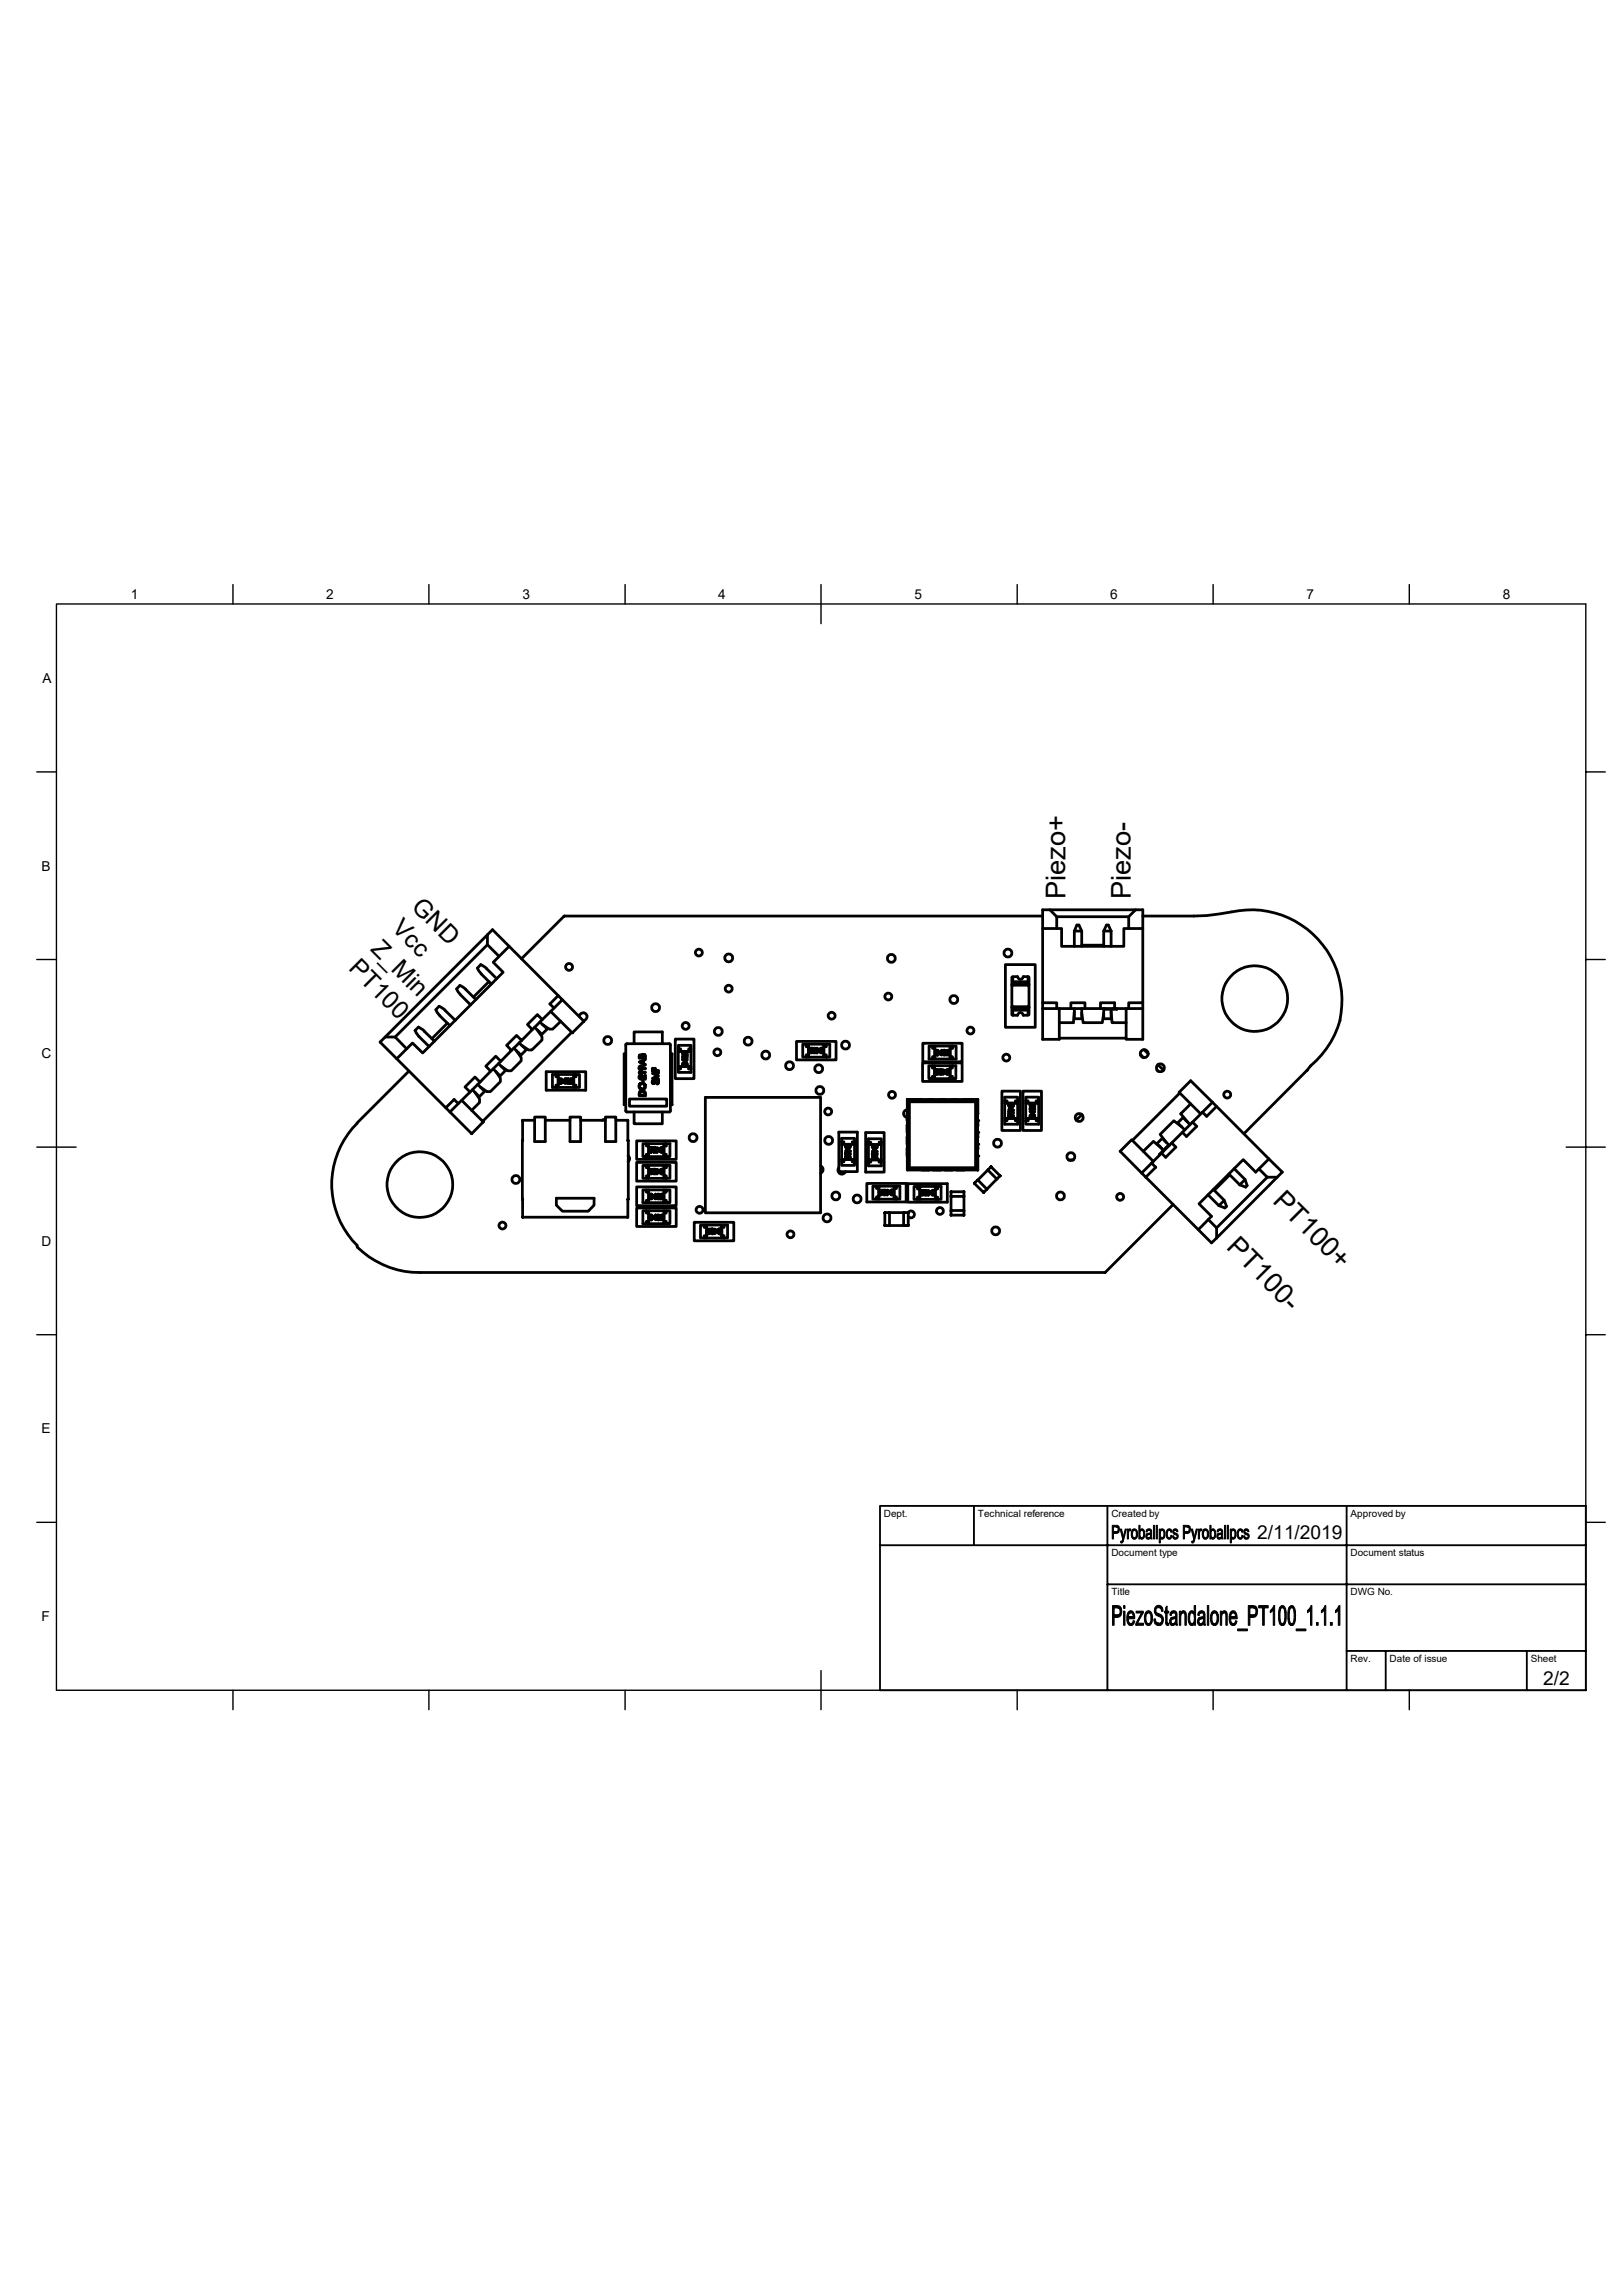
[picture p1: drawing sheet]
<svg xmlns="http://www.w3.org/2000/svg" width="297mm" height="420mm" viewBox="0 0 297 420" stroke-linecap="round" stroke-linejoin="round" font-family="sans-serif">
<defs><g id="words">
<g font-size="5">
<text x="195" y="164.6" transform="rotate(-90 195 164.6)">Piezo+</text>
<text x="207" y="164.6" transform="rotate(-90 207 164.6)">Piezo-</text>
<text x="232.7" y="220" transform="rotate(45 232.7 220)">PT100+</text>
<text x="224.2" y="228.5" transform="rotate(45 224.2 228.5)">PT100-</text>
</g>
<g font-size="4.5">
<text x="75.1" y="166.1" transform="rotate(45 75.1 166.1)">GND</text>
<text x="67.6" y="173.8" transform="rotate(45 67.6 173.8)">Z_Min</text>
<text x="71.5" y="170.1" transform="rotate(45 71.5 170.1)">Vcc</text>
<text x="63.6" y="177.4" transform="rotate(45 63.6 177.4)">PT100</text>
</g>
<g font-size="3.5">
<text x="230.1" y="281.7">2/11/2019</text>
<text x="282.4" y="308.4">2/2</text>
</g>
<g font-size="2.5">
<text x="24" y="109.6">1</text>
<text x="59.7" y="109.6">2</text>
<text x="95.6" y="109.6">3</text>
<text x="131.4" y="109.6">4</text>
<text x="167.3" y="109.6">5</text>
<text x="203.2" y="109.6">6</text>
<text x="239.1" y="109.6">7</text>
<text x="275" y="109.6">8</text>
<text x="7.7" y="125">A</text>
<text x="7.6" y="159.3">B</text>
<text x="7.6" y="193.7">C</text>
<text x="7.6" y="228">D</text>
<text x="7.6" y="262.3">E</text>
<text x="7.6" y="296.6">F</text>
</g>
<g font-size="1.8">
<text x="161.8" y="277.6">Dept.</text>
<text x="178.9" y="277.6">Technical reference</text>
<text x="203.4" y="277.6">Created by</text>
<text x="247.1" y="277.6">Approved by</text>
<text x="203.4" y="284.8">Document type</text>
<text x="247.1" y="284.8">Document status</text>
<text x="203.4" y="292">Title</text>
<text x="247.1" y="292">DWG No.</text>
<text x="247.1" y="304.2">Rev.</text>
<text x="254.3" y="304.2">Date of issue</text>
<text x="280.1" y="304.2">Sheet</text>
</g>
</g></defs>
<g fill="none" stroke="#000" stroke-width=".51">
<path d="M89.2 172.9l-16.9 16.9M89.2 171.1l-18.7 18.7M89.5 179.6l-2.8 2.9M90.9 179.1l-1.9-1.9-1-.7-.6 .7 .1 .3 .5 .6 1.9 2M93.2 173.2l-3.1-3.1-.9 1v1.8l2.1 2.1M184 176.5h5.4v11.5h-5.4zM185.3 178.8h-.1v1.3M186.2 178.7h-.9v1h2.8v-1h-.8M186.2 178.7a.51 .51 0 0 0 .5 .5 .51 .51 0 0 0 .5-.5M188.1 178.8h.2v1.3M190.8 169.9h3.5v3.3h11.4v-3.3h3.4v13.6h-2.6v1.1M190.8 167.6h-87.5l-7.9 7.9"/>
<path d="M192.1 166.5l1.3 1.3v2.1M193.4 167.8h13.1M196.6 170.4v2.8M197.1 169.3h.3l.6 1.1h-1.4zM198 170.4v2.8M198 173h4M202 170.4v2.8M202.5 169.3h.3l.5 1.1h-1.3zM203.3 170.4v2.8M206.5 169.9v-2.1l1.3-1.3h1.3v3.4M207.8 166.5h-17v23.7h3v-5.6M209.1 167.6h9.4a51 51 0 0 0 8.2-.9 16.6 16.6 0 0 1 18.5 20"/>
<path d="M72.6 193.8l2.9-2.9 1.8 1.8 14.8-14.8-1.8-1.8 2.9-2.9 9 9-1.6 1.5 .8 .8-2.2 2.1-.9-.9-1.8 1.8 .9 .9-1.9 2-1-.9-1.8 1.8 .9 .9-1.9 2-1-.9-1.8 1.8 .9 .9-2 2-.9-.9-1.8 1.8 .9 1-2.1 2.1-.8-.8-1.5 1.5M74.4 191.9l-2.1-2.1h-1.8l-.9 .9 16.7 16.8 2.1-2.2-3.9-3.9M74.8 196l-9.5 9.5M79.5 190.5l-2.1-2-.8-.5-.7 .6 .3 .5 2.3 2.4M81.9 187.2l-2.9 2.9M83.3 186.7l-2.1-2-.9-.5-.5 .6 .1 .4 .6 .7 1.8 1.8M86.9 199.9l.9 1.2v.7l-1.5 1.4M87.1 182.9l-1.9-1.9-1-.7-.6 .7 .1 .4 2.4 2.5M87.4 198.5l1.3 1.2-1 1-1.3-1.3M87.8 198l-1.8 1.9M90.7 196.1l.9 1.2v.7l-1.9 1.8h-.6l-1.2-.9M91.2 194.6l1.3 1.3-1 1-1.2-1.3"/>
<path d="M91.7 194.2l-1.9 1.8M94.5 192.3l.9 1.2v.6l-1.8 1.9h-.7l-1.2-.9M95 190.8l1.3 1.3-1 1-1.3-1.3M95.5 190.4l-1.9 1.8M98.3 188.5l.9 1.2v.6l-1.9 1.9h-.6l-1.2-.9M98.8 187l1.3 1.3-1 1-1.3-1.3M99.2 186.6l-1.8 1.8M99.9 196.1h7.3v3.4h-7.3zM101.7 196.6v.5h.5v1.5h-.5v.4M102.2 196.6h2.8v2.4h-2.8zM102.2 182.2l.7 .8-1.5 1.5M102.2 196.6h-1.1v2.4h1.1"/>
<path d="M102.3 197.6l.2-.2a.45 .45 0 0 1 .4 .4 .45 .45 0 0 1-.4 .5 .52 .52 0 0 1-.2-.7zM102.4 197.6l.3-.1 .1 .1v.5l-.1 .1-.3-.1zM102.6 186.9l-1.5 1.4h-.6l-1.2-.8M102.9 183l3.9 3.9-2.1 2.1-3.9-3.9M103.4 197.6v.4h-.3zM103.4 197.4l.1 .7-.1 .2v-.2h-.4zM103.7 197.6l.1-.1h.3v.5l-.1 .2-.3-.1zM103.8 197.4h.3l.1 .4a.34 .34 0 0 1-.1 .4 .34 .34 0 0 1-.4 0l-.1-.6zM104.4 197.4h.3l.2 .2-.1 .2-.3 .4 .4 .1h-.6l.5-.6-.1-.2-.4 .2zM104.6 188.9l-16.3 16.3M105 197.1h.4v-.5h.6v2.4h-.6v-.4h-.4zM105 199h.4"/>
<path d="M105 196.6h.4M106 186a.72 .72 0 0 1 .7-.7 .72 .72 0 0 1 .7 .7 .72 .72 0 0 1-.6 .8M114.5 192.9h-.3v9.3h.3M114.6 191.1h8v12.4h-8zM116 191v-2.2h5.2v2.2M117 194.4l1.1-.6v.1l-.4 .2v.5l.4 .2v.1zM117 196.2l1.1 .1h-1v.2zM117 195.2l.4-.1 .7 .4v.1l-.5-.3v.3a.36 .36 0 0 1-.4 .2 .36 .36 0 0 1-.3-.3zM117 196.9l.4-.1 .6 .5v-.5h.1v.7l-.7-.6-.3 .1v.3l.2 .2-.2-.1-.2-.2zM117 193.1l.3-.1 .2 .2 .1-.2h.3l.2 .3v.3h-1.1zM117.1 193.2l.2-.1 .1 .4h-.3zM117.1 199.7a.62 .62 0 0 1 1 .5v.3h-1.1z"/>
<path d="M117.1 195.2a.26 .26 0 0 1 .4 .1 .26 .26 0 0 1-.2 .4l-.2-.2zM117.2 194.4l.4-.3v.5zM117.2 199.8l.2-.1h.4l.2 .3v.4h-.9zM117.6 197.7h.1v.4h-.1zM117.6 193.1h.3l.1 .4h-.4zM119.3 197.9l.2-.2 .1 .1-.1 .4h.2a.57 .57 0 0 1 .7-.4l.1 .4-.2 .2v-.6h-.2l-.5 .5-.2-.1zM119.4 195.5l.1 .4h.3l.1-.4v.4h.6v.1h-1.1zM119.4 196.4l1.1-.1v.1l-.8 .1 .8 .4-.8 .4 .8 .2-1.1-.1 .9-.5zM122.7 192.9h.3v9.3h-.3M123.6 190.2h3.4v7.2h-3.4zM124.1 192.4h2.3v2.8h-2.3zM124.1 191.3h2.3v.6h-.4v.5h-1.5v-.5h-.4z"/>
<path d="M124.1 195.6h.4v-.4h1.5v.4h.4M124.1 191.9v.5M124.1 195.2v.4M124.9 192.6l.3-.1 .4 .4v-.4h.2v.6l-.6-.5-.2 .1 .1 .3h-.1zM124.9 193.9l.7-.1 .2 .2h-.2v.4zM124.9 194.6l.2-.1a.46 .46 0 0 1 .7 .4l-.5 .2a.37 .37 0 0 1-.4-.5zM124.9 193.3l.7-.1 .2 .3-.2 .2h-.5l-.2-.2zM125 194.7l.1-.1h.5l.1 .2-.1 .1-.4 .1-.2-.1zM125 193.3h.1a.38 .38 0 0 1 .6 .2l-.1 .1h-.5l-.1-.1zM125.1 194h.4v.2zM126.4 195.2v1.1h-2.3v-.7M126.4 191.9v.5"/>
<path d="M145.8 190.6h7.2v3.4h-7.2zM146.9 191.1h.6v.5h.5v1.4h-.5v.5h-.6zM147.5 191.1h.5M147.5 193.5h.5M148 191.1h2.7v2.4h-2.7zM148.1 191.8h.5l-.4 .5 .1 .3 .3-.2-.1 .3-.4-.1 .1-.4 .3-.3zM148.8 191.9h.1a.43 .43 0 0 1 .5 .4 .43 .43 0 0 1-.5 .4l-.2-.3zM148.8 192l.3-.1 .1 .2-.1 .5-.3-.2zM149.5 191.8l.1 .2h.4l-.5 .7-.1-.6zM149.6 192.1h.2l-.2 .4zM150.2 191.9l.3-.1 .1 .2v.5l-.1 .2-.4-.2zM150.2 191.9h.2l.1 .1v.5l-.1 .1h-.2l-.1-.2z"/>
<path d="M150.7 191.1h1.1v2.4h-.6M150.7 193.5h.5M151.2 191.1v.5h-.5v1.4h.5v.5M168.8 194.5h7.3v3.4h-7.3zM168.9 190.9h7.2v3.4h-7.2zM170 195h.6v.5h.4v1.5h-.4v.4h-.6zM170.6 195h.4M170.6 197.4h.4M170.6 191.4v.5h.5v1.5h-.5v.4M170.6 191.4h-.6v2.4h1.1M170.6 191.4h.5M171 195h2.9v2.4h-2.9z"/>
<path d="M171.1 191.4h2.8v2.4h-2.8zM171.2 195.7h.5l-.5 .6 .2 .3 .3-.3-.1 .3a.29 .29 0 0 1-.5-.1 .29 .29 0 0 1 .2-.5l.2-.2zM171.3 192.3l.3-.1 .2 .2-.1 .6-.3 .1a.39 .39 0 0 1-.2-.7zM171.3 192.4l.1-.1a.34 .34 0 0 1 .3 .4 .34 .34 0 0 1-.3 .3zM171.9 195.8l.2-.1 .2 .1 .1 .6a.32 .32 0 0 1-.4 .2 .32 .32 0 0 1-.2-.4zM172 195.8l.3 .2v.4l-.2 .2-.2-.3zM172.3 192.4v.4h-.3zM172.3 192.2v.6l.2 .1-.2 .2v-.2h-.4zM172.6 195.7v.3h.5l-.5 .6-.1-.6zM172.6 192.3l.3-.1 .2 .2v.5l-.2 .2-.3-.2zM172.6 196h.3l-.3 .4zM172.6 192.4l.2-.1 .2 .1v.5a.22 .22 0 0 1-.2 .1 .22 .22 0 0 1-.2-.2z"/>
<path d="M173.2 195.8l.2-.1 .3 .1a.51 .51 0 0 1-.2 .8l-.3-.1zM173.2 192.4a.29 .29 0 0 1 .5-.1 .29 .29 0 0 1-.1 .4l-.2 .3 .4 .1h-.6l.5-.6-.1-.2h-.2l-.1 .2zM173.3 195.8h.2l.2 .2-.1 .4-.2 .2-.2-.2zM173.9 191.9h.4v-.5h.7v2.4h-.7v-.4h-.4zM173.9 195h1v2.4h-.6M173.9 193.8h.4M173.9 191.4h.4M173.9 197.4h.4M174.3 195v.5h-.4v1.5h.4v.4M183.3 199.7h3.4v7.2h-3.4zM185.2 180.3h3.1v3.9h-3.1zM185.2 184.2v.2h3.1"/>
<path d="M185.2 180.3v-.2h3.1v.2M185.2 184.4v1.3h.1M186.2 185.8h-.9v-.9h2.8v.9h-.8M186.2 185.8a.51 .51 0 0 1 .5-.5 .51 .51 0 0 1 .5 .5M187.2 199.7h3.4v7.2h-3.4zM188.3 184.4v1.3h-.2M188.3 184.2v.2M190.8 183.5h2.6v1.1M190.8 184.6h18.3M193.8 190h12.3M196 184.6v-1.1h2.5v1.1M196.6 184.6v1.8h1.4v-1.8"/>
<path d="M196.6 185.1l-.2 2.1h-2.6M198 185.4l.2 1.8h3.5l.3-1.8M201.4 184.6v-1.1h2.6v1.1M202 184.6v1.8h1.3v-1.7M202.1 184.6v.1h1.5M203.3 185.1l.2 2.1h2.6M203.6 184.6v.1h.8v-.1M208.7 192.9l.6 .7M209.1 183.5v6.7h-3v-5.6M209.3 192.1l.8 .8M211.7 195.8l.2 .2M211.9 194.8l1 1.1"/>
<path d="M245.2 186.7a16.9 16.9 0 0 1-5.4 8.4l-.6 .8-11.6 11.6M65.4 205.6a15.7 15.7 0 0 0 0 22.3M83.9 202l-1.6 1.5M95.6 219.4v3.4h19.3v-3.4M95.7 208.7v10.8M97.8 204.4h2v4.5h-2zM97.8 205h-2.2v3.8M99.8 205h4.5M101.8 219.3h6.9v1.3l-1 1.1h-4.8l-1.1-1.1zM104.3 204.4h2v4.5h-2zM106.3 205h4.5M110.7 204.9l-.5 .1"/>
<path d="M110.8 204.4h1.9v4.5h-1.9zM112.7 205h2.2v3.8M114.9 208.7v10.8M114.9 211.5a.66 .66 0 0 1 0 1.1M115.2 201.1h6.8v1.3h-6.8zM116 203.5v2.2h5.2v-2.2M116.5 217.2h7.2v3.4h-7.2zM116.5 212.7h7.2v3.5h-7.2zM116.5 208.8h7.2v3.4h-7.2zM117.6 213.3h.7v.4h.4v1.5h-.4v.4h-.7zM117.6 209.3h.7v.4h.4v1.5h-.4v.5h-.7zM118.3 217.8v.4h.4v1.5h-.4v.4"/>
<path d="M118.3 217.8h-.7v2.3h1.1M118.3 213.3h.4M118.3 209.3h.4M118.3 217.8h.4M118.3 215.6h.4M118.3 211.7h.4M118.7 217.8h2.8v2.3h-2.8zM118.7 213.3h2.8v2.3h-2.8zM118.7 209.3h2.8v2.4h-2.8zM118.8 214h.6l-.5 .5 .1 .3h.2l.1-.2-.1 .2-.4-.1v-.2l.4-.4zM118.8 210h.6l-.5 .5 .1 .3h.2l.1-.2-.2 .3a.28 .28 0 0 1-.2-.2 .28 .28 0 0 1 0-.3l.3-.3zM118.9 218.7l.1-.2 .4 .2v.5l-.1 .2h-.3l-.1-.2z"/>
<path d="M119 218.7l.2-.1 .1 .2-.1 .5-.3-.1zM119.5 214h.2a.47 .47 0 0 1 .4 .2 .47 .47 0 0 1-.1 .5l-.1 .1-.4-.1zM119.5 210.1l.3-.1 .2 .1a.54 .54 0 0 1-.3 .8 .56 .56 0 0 1-.2-.8zM119.6 214.1l.2-.1 .2 .2v.4l-.2 .2-.3-.2zM119.6 210.1h.2l.2 .1-.1 .6h-.3l-.1-.2zM119.9 218.7v.4h-.2zM120 218.5v.6l.1 .1h-.1l-.1 .2v-.2h-.4zM120.2 214l.1 .2h.4l-.5 .6zM120.2 210l.1 .2h.4l-.5 .7zM120.3 218.6a.45 .45 0 0 1 .5 .3 .45 .45 0 0 1-.2 .5l-.4-.2zM120.3 218.7h.1a.31 .31 0 0 1 .3 .3 .31 .31 0 0 1-.4 .2zM120.3 214.2h.3l-.3 .4z"/>
<path d="M120.3 210.3h.3l-.3 .4zM120.9 214.1l.1-.1 .3 .1a.47 .47 0 0 1-.2 .7l-.3-.1zM120.9 210.1l.1-.1 .3 .1 .1 .6a.28 .28 0 0 1-.4 .2 .28 .28 0 0 1-.2-.3zM120.9 214.2l.1-.2 .3 .2v.4l-.1 .2-.3-.1zM120.9 210.2l.2-.1 .2 .1-.1 .6-.3-.1zM120.9 218.6h.5v.3l-.4 .4h.4v.1h-.6l.5-.5-.1-.3-.3 .2zM121.5 218.2h.4v-.4h.7v2.3h-.7v-.4h-.4zM121.5 213.3h1.1v2.3h-.7M121.5 209.3h1.1v2.4h-.7M121.5 217.8h.4M121.5 215.6h.4M121.5 211.7h.4"/>
<path d="M121.9 213.3v.4h-.4v1.5h.4v.4M121.9 209.3v.4h-.4v1.5h.4v.5M129.1 200.8h21.1v21.2h-21.1zM150.2 213.4a.75 .75 0 0 1 .4 .6 .75 .75 0 0 1-.4 .7M153.5 207.2h3.4v7.2h-3.4zM153.5 213.7a.72 .72 0 0 0 .2 1.1 .72 .72 0 0 0 1-.4M154 212.6h.4v-.4h1.6v.4h.4v.7h-2.4zM154 209.4h2.4v2.8h-2.4M154 209h.4v.4h1.6v-.4h.4M154.7 211l.2-.1a.45 .45 0 0 1 .7 .3l-.3 .3h-.3l-.3-.2zM154.7 211.5l.5 .5h.2l.1-.2-.2-.3a.28 .28 0 0 1 .3 .4 .28 .28 0 0 1-.4 .2l-.4-.4-.1 .4zM154.7 209.7l.2-.1h.5l.2 .2-.1 .3h-.6l-.2-.2z"/>
<path d="M154.8 211l.6-.1 .1 .3-.1 .1-.4 .1-.2-.1zM154.9 209.7l.2-.1a.28 .28 0 0 1 .4 .2 .28 .28 0 0 1-.4 .3l-.3-.2zM154.9 210.2l.7 .5h-.9l.2-.1zM155 210.4l.4 .2h-.4zM156.4 209v-.7h-2.4v4.3M156.4 209v.4M156.4 212.2v.4M158.4 207.3h3.4v7.2h-3.4zM158.6 216.6h7.2v3.4h-7.2zM158.9 212.3v-2.8h2.4v2.8M158.9 212.7h.4v-.4h1.6v.4h.4v.7h-2.4zM158.9 209h.4v.5h1.6v-.5h.4"/>
<path d="M158.9 212.3h2.4M158.9 212.3v.4M159.6 211.1a.52 .52 0 0 1 .9 .2l-.2 .2h-.4l-.3-.1zM159.6 211.6l.4 .3a.24 .24 0 0 0 .4 .1 .24 .24 0 0 0-.2-.4 .29 .29 0 0 1 .2 .5 .29 .29 0 0 1-.5-.1l-.2-.2-.1 .4zM159.6 209.8l.7-.2a.3 .3 0 0 1 .2 .3 .3 .3 0 0 1-.2 .3l-.5-.1-.2-.2zM159.7 209.8l.5-.1 .2 .2-.2 .2h-.3l-.2-.1zM159.7 217.1h.7v.4h.4v1.5h-.4v.5h-.7zM159.8 211h.3a.25 .25 0 0 1 .3 .1 .25 .25 0 0 1 0 .3h-.6l-.1-.2zM159.9 210.3l.6 .4h-.6v.2l-.3-.2h.3zM159.9 210.4l.4 .3h-.4zM160.4 217.1h.4M160.4 219.5h.4"/>
<path d="M160.8 217.1h2.8v2.4h-2.8zM160.9 217.8h.6l-.5 .7 .2 .1 .2-.2a.25 .25 0 0 1-.4 .3 .25 .25 0 0 1 0-.5l.3-.3zM161.3 209v-.6h-2.4v1.1M161.3 209v.5M161.3 212.3v.4M161.7 217.8a.43 .43 0 0 1 .5 .4 .43 .43 0 0 1-.4 .5l-.2-.3zM161.7 217.9l.2-.1 .2 .3v.4l-.2 .1-.2-.2zM162.3 217.8l.1 .2h.4l-.5 .7v-.6h-.1zM162.4 218.1h.3l-.3 .3zM163 217.8h.2a.46 .46 0 0 1 .3 .4 .46 .46 0 0 1-.3 .5 .52 .52 0 0 1-.2-.9zM163 217.9l.2-.1 .2 .2-.1 .6-.3-.1zM163.6 217.1h1.1v2.4h-.7"/>
<path d="M163.6 219.5h.4M164 217.1v.4h-.4v1.5h.4v.5M166 201.2h12.9l-.4 .4h-12.1zM166 210.2v1.3M166 208.1v1.3M166 206v1.2M166 203.8v1.3M166 203.1a.72 .72 0 0 0-.7 .7 .72 .72 0 0 0 .7 .7M166.1 216.6h7.3v3.4h-7.3zM166.4 201.6v12.1M167.3 217.1h.6v.5h.4v1.5h-.4v.4h-.6zM167.9 217.1h.4"/>
<path d="M167.9 219.5h.4M168.3 217.1h2.9v2.4h-2.9zM168.4 217.8h.6l-.5 .6 .1 .3 .4-.3-.2 .3h-.2l-.2-.1 .1-.3 .3-.4zM168.6 214.1h1.3M168.7 201.2h-2.7v12.9h12.9M169.2 217.9l.3-.1a.67 .67 0 0 1 0 .9l-.4-.1zM169.2 218l.3-.1 .1 .2v.4l-.1 .2-.3-.1zM169.8 217.8l.1 .3h.4l-.4 .6-.1-.6zM169.9 201.2h.9M169.9 218.1h.3l-.3 .4zM170.5 218l.3-.2 .2 .2v.6l-.1 .1a.43 .43 0 0 1-.5-.2 .43 .43 0 0 1 .1-.5zM170.6 218h.3v.4l-.1 .3-.3-.2z"/>
<path d="M170.7 214.1h1.4M171.2 217.1h1v2.4h-.6M171.2 219.5h.4M171.6 217.1v.5h-.4v1.5h.4v.4M172 201.2h.9M172.9 214.1h1.3M174 218.9h2.4v2.6h-2.4zM174 218.9v-.8h2.4v.8M174 218.9h.1M174.1 218.1h-.1M174.2 201.2h.9M175 214.1h1.4"/>
<path d="M176.3 218.1h.1M176.4 201.2h2.5M176.4 218.9h-.1M178.4 216.5v.1M178.5 213.7h-12.1l-.4 .4M178.9 201.2v12.9l-.4-.4v-12.1M178.9 214.1h.1M178.9 216h.1M178.9 215.9l1.9-1.8 1.6 1.7-1.8 1.8zM178.9 209.4l.1 .8M178.9 207.2l.1 .9M178.9 205.1l.1 .9"/>
<path d="M178.9 201.2l.1 2.6M178.9 211.5v2.6M178.9 215.9l-.6 .6 1.7 1.7M180 218.2h.1M180.6 217.6v.1M180.6 217.6l-.6 .6M180.8 214.1v.1M181.3 213.6l-.5 .5M181.3 213.6h.1M181.4 213.6l1.6 1.5M182.4 215.7h.1M183 215.2l-.6 .6"/>
<path d="M183 215.1v.1M183.9 201.9h2.3v2.8h-2.3zM183.9 201.5h.4v.4h1.5v-.4h.4M183.9 204.7v.4M184.6 203.5a.49 .49 0 0 1 .5-.2 .49 .49 0 0 1 .4 .4l-.3 .2h-.4l-.2-.1zM184.6 204l.6 .5 .2-.1v-.2l-.2-.1 .1-.1 .2 .4-.4 .2-.4-.4-.1 .4zM184.6 202.2l.2-.2h.4l.2 .1 .1 .3-.2 .2h-.4l-.3-.1zM184.7 203.5l.5-.1 .2 .3-.6 .1-.1-.1zM184.7 202.1h.6l.1 .3-.1 .1a.35 .35 0 0 1-.4 0 .35 .35 0 0 1-.2-.3zM184.8 202.7l.7 .5h-.9l.2-.1zM184.9 202.8l.4 .3h-.4zM186.2 204.7v1h-2.3v-.6h.4v-.4h1.5v.4h.4"/>
<path d="M186.2 201.5v-.7h-2.3v1.1M186.2 201.5v.4M187.7 201.9h2.4v2.8h-2.4zM187.7 200.8h2.4v.7h-.5v.4h-1.5v-.4h-.4zM187.7 205.1h.4v-.4h1.5v.4h.5M187.7 201.5v.4M187.7 204.7v.4M188.5 203.4h.6v-.1l.3 .2h-.3v.4zM188.5 202.8l.2-.1h.5a.4 .4 0 0 1-.1 .6 .4 .4 0 0 1-.5-.2zM188.5 202.1l.3-.1 .5 .4 .1-.4v.6l-.6-.5-.2 .1v.2h.2l-.2 .1zM188.5 204.1l.3-.1h.4l.2 .4-.3 .2h-.4l-.2-.2zM188.6 204.2l.5-.2a.21 .21 0 0 1 .2 .2 .21 .21 0 0 1-.2 .3l-.5-.1z"/>
<path d="M188.6 202.9l.1-.1a.39 .39 0 0 1 .6 .1l-.1 .2-.4 .1-.2-.2zM188.7 203.5h.4v.3zM190.1 204.7v1h-2.4v-.6M190.1 201.5v.4M195.5 212.3h1M198 204l-1.1 1M210.7 212.9l.8 .7-1.8 1.8M211.1 212.6l-4-4-2.1 2.1 4.7 4.7M212.6 210.2l-1.5-1.3-1.9 1.8M212.8 210.8l-.1-.1-.5 .5 .1 .1M213.9 209.7l-.1-.1-1.1 1.1M214 209.6l-1.3-1.3-1 1 1.2 1.2"/>
<path d="M214.4 209.2l.8 .7-1.9 1.9-.7-.8M215.9 200l-8.7 8.7M216.2 206.2l-1.4-1.1-2.5 2.5 1.1 1.4M217.8 205.8l-1.3-1.3-1 1 1.3 1.3M217.9 202l-1.8 1.8 1.3 1.6M218.2 205.4l.8 .7-1.9 1.9-.7-.8M221.1 218.7l2 1.9M221.9 201.7l10.3 10.4M221.9 201.7l-4-3.9-2.1 2.1 3.9 3.9M221.9 201.7l-13 13M222 217.7l2 2M222.6 202.5l-1.8 1.8-.8-.8"/>
<path d="M224.9 214.8l2 2M225 215l-2.8 2.8M225.8 213.9l2 2M226.9 216.8l.9-.9 .4 1.1-.2 .3zM230.4 213.9l1.5 1.5M231.9 215.4h1.8M231.9 215.4l-9.3 9.3M232.2 212.1l2.5 2.4-12.1 12.1M232.2 212.1l-2.4 2.4-2.3-2.3-8.1 8.1 2.3 2.3-2.4 2.4-9.6-9.6M65.3 228l.1 .2M116.5 221.1h7.2v3.4h-7.2zM118.3 221.6v.4h.4v1.5h-.4v.4"/>
<path d="M118.3 221.6h-.7v2.3h1.1M118.3 221.6h.4M118.7 221.6h2.8v2.3h-2.8zM118.9 222.4l.3-.1 .2 .3v.5l-.2 .2a.54 .54 0 0 1-.3-.9zM119 222.5l.1-.1 .2 .1v.5a.22 .22 0 0 1-.2 .1 .22 .22 0 0 1-.2-.1zM119.9 222.5v.4h-.2zM120 222.3v.6l.1 .1h-.1l-.1 .2v-.2h-.4zM120.2 222.5l.4-.1 .1 .4a.28 .28 0 0 1-.2 .4l-.3-.1zM120.4 222.5v-.1a.36 .36 0 0 1 .3 .4 .36 .36 0 0 1-.3 .3l-.2-.3zM120.9 222.5a.3 .3 0 0 1 .5-.1 .3 .3 0 0 1-.2 .5l-.2 .2 .4 .1h-.6l.5-.5-.1-.3-.3 .2zM121.5 222h.4v-.4h.7v2.3h-.7v-.4h-.4zM121.5 223.9h.4"/>
<path d="M121.5 220.1h.4M121.5 221.6h.4M127 223.7h7.3v3.4h-7.3zM128.2 224.2h.7v.4h.4v1.5h-.4v.5h-.7zM128.9 224.2h.4M128.9 226.6h.4M129.3 224.2h2.8v2.4h-2.8zM129.4 224.9h.6l-.5 .5v.2l.2 .1 .1-.2a.24 .24 0 0 1-.2 .3 .24 .24 0 0 1-.2-.4l.4-.4zM130.1 225l.3-.1a.55 .55 0 0 1 .2 .7l-.2 .2-.3-.1zM130.1 225.1l.1-.1a.34 .34 0 0 1 .4 .3 .34 .34 0 0 1-.4 .4zM130.8 224.9l.1 .2h.4l-.5 .7v-.6h-.1zM130.9 225.2h.2l-.2 .4z"/>
<path d="M131.4 225l.2-.1a.48 .48 0 0 1 .4 .4 .48 .48 0 0 1-.4 .5 .6 .6 0 0 1-.2-.8zM131.5 225h.2a.35 .35 0 0 1 .2 .4 .35 .35 0 0 1-.4 .3zM132.1 224.2h1v2.4h-.6M132.1 226.6h.4M132.5 224.2v.4h-.4v1.5h.4v.5M161.9 224.3h.9M161.9 224.2l.1 .1M162 222h-.1M162.7 222h.1M162.7 224.2v.1M162.8 221.9h2.6v2.4h-2.6zM162.8 221.9h-.9v2.4"/>
<path d="M165.4 224.3h.8M165.4 221.9h.8v2.4M165.4 224.2v.1M165.4 222h.1M166.2 222a.63 .63 0 0 1 .9-.2 .63 .63 0 0 1 0 1 .63 .63 0 0 1-.9-.2M166.2 224.2v.1M174 221.5v.9h2.4v-.9M174 222.3l.1 .1M174.1 221.6h-.1M176.3 221.6h.1M176.4 222.3l-.1 .1M214.7 220.4l-12.5 12.5h-125.4a16.1 16.1 0 0 1-11.4-4.7"/>
<path d="M219.3 225l2.4 2.5 .9-.9M221.1 223.2l1.5 1.5M222.6 224.7v1.9M223.1 220.6l.9-.9 .5 1.1-.3 .3z"/>
<circle cx="104.1" cy="177" r=".63"/>
<circle cx="127.9" cy="174.3" r=".63"/>
<circle cx="133.3" cy="175.3" r=".72"/>
<circle cx="163.1" cy="175.4" r=".72"/>
<circle cx="184.4" cy="174.4" r=".72"/>
<circle cx="111.2" cy="190.4" r=".72"/>
<circle cx="117.5" cy="198.8" r=".49"/>
<circle cx="117.5" cy="198.8" r=".62"/>
<circle cx="120" cy="184.4" r=".72"/>
<circle cx="125.5" cy="187.7" r=".63"/>
<circle cx="131.3" cy="192.6" r=".63"/>
<circle cx="131.4" cy="188.8" r=".72"/>
<circle cx="133.4" cy="180.9" r=".63"/>
<circle cx="136.9" cy="190.5" r=".72"/>
<circle cx="140.1" cy="193.1" r=".72"/>
<circle cx="144.5" cy="195" r=".72"/>
<circle cx="149.8" cy="195.6" r=".72"/>
<circle cx="150" cy="199.5" r=".72"/>
<circle cx="152.2" cy="185.9" r=".63"/>
<circle cx="154.7" cy="191.2" r=".72"/>
<circle cx="162.6" cy="182.4" r=".63"/>
<circle cx="174.5" cy="182.9" r=".72"/>
<circle cx="177.6" cy="188.6" r=".63"/>
<circle cx="184.2" cy="193.5" r=".63"/>
<circle cx="209.4" cy="192.8" r=".72"/>
<circle cx="212.3" cy="195.4" r=".72"/>
<circle cx="229.6" cy="182.7" r="6"/>
<circle cx="76.8" cy="216.8" r="6"/>
<circle cx="94.4" cy="215.8" r=".72"/>
<circle cx="126.8" cy="208.2" r=".72"/>
<circle cx="151.6" cy="203.4" r=".63"/>
<circle cx="151.6" cy="208.7" r=".72"/>
<circle cx="152.9" cy="218.8" r=".72"/>
<circle cx="156.8" cy="219.4" r=".72"/>
<circle cx="163.2" cy="200.4" r=".63"/>
<circle cx="182.5" cy="209.2" r=".72"/>
<circle cx="194.1" cy="218.8" r=".72"/>
<circle cx="196" cy="211.7" r=".72"/>
<circle cx="197.5" cy="204.5" r=".72"/>
<circle cx="205" cy="219" r=".63"/>
<circle cx="224.6" cy="200.3" r=".63"/>
<circle cx="92" cy="224.3" r=".63"/>
<circle cx="128" cy="221.4" r=".63"/>
<circle cx="144.7" cy="225.9" r=".63"/>
<circle cx="151.3" cy="222.9" r=".72"/>
<circle cx="172" cy="221.6" r=".63"/>
<circle cx="182.2" cy="225.2" r=".72"/>
</g>
<g fill="#000">
<circle cx="169.9" cy="201.2" r=".25"/>
<circle cx="172" cy="201.2" r=".25"/>
<circle cx="174.2" cy="201.2" r=".25"/>
<circle cx="176.4" cy="201.2" r=".25"/>
<circle cx="178.9" cy="205.1" r=".25"/>
<circle cx="178.9" cy="209.4" r=".25"/>
<circle cx="178.9" cy="207.2" r=".25"/>
<circle cx="178.9" cy="211.5" r=".25"/>
</g>
<g fill="none" stroke="#000" stroke-width=".25">
<path d="M10.3 110.5h279.9v198.8h-279.9zM42.6 107v3.5M78.5 107v3.5M114.4 107v3.5M150.2 107v7.1M186.1 107v3.5M222 107v3.5M257.9 107v3.5M6.7 141.3h3.6M290.2 141.3h3.6M6.7 175.6h3.6M290.2 175.6h3.6"/>
<path d="M6.7 209.9h7.2M286.6 209.9h7.2M6.7 244.3h3.6M290.2 244.3h3.6M6.7 278.6h3.6M290.2 278.6h3.6M42.6 309.3v3.6M78.5 309.3v3.6M114.4 309.3v3.6M150.2 305.7v7.2M186.1 309.3v3.6M222 309.3v3.6"/>
<path d="M257.9 309.3v3.6"/>
</g>
<path d="M161 275.6h129.2v33.7h-129.2zM178.2 275.6v7.2M202.6 275.6v33.7M246.4 275.6v33.7M161 282.8h129.2M202.6 289.9h87.6M246.4 302.1h43.8M253.6 302.1v7.2M279.4 302.1v7.2" fill="none" stroke="#000" stroke-width=".34"/>
<g fill="#000" stroke="#000" stroke-width=".18">
<path d="M203.5 279.1h.9l.4 .3h-1v.9l.9 .1-.2 .2h-.7v1h-.3z" fill-rule="evenodd"/>
<path d="M204.2 279.4h.6l.1 .6-.2 .4-.9-.1h.5l.3-.1v-.5l-.2-.3z" fill-rule="evenodd"/>
<path d="M205 279.8h.2l.4 1.5-.2 .3z" fill-rule="evenodd"/>
<path d="M205.9 279.8h.2l-.5 2.2-.4 .1 .2-.2z" fill-rule="evenodd"/>
<path d="M206.3 279.8h.2v.3h.2l-.2 .4v1.1h-.2z" fill-rule="evenodd"/>
<path d="M206.6 279.9l.3-.1v.4l-.4-.1z" fill-rule="evenodd"/>
<path d="M207.3 279.9l.4-.1 .4 .4 .1 .9-.5 .6h-.3l-.2-.3h.5l.2-.2v-1l-.3-.2h-.4z" fill-rule="evenodd"/>
<path d="M208.4 279.1h.2v.9h.3l-.3 .4v.7l.2 .3h-.2v.2h-.2z" fill-rule="evenodd"/>
<path d="M208.6 280l.3-.2 .3 .1a1.57 1.57 0 0 1 .2 1.5l-.4 .3-.4-.2 .4-.1a.93 .93 0 0 0 0-1.4z" fill-rule="evenodd"/>
<path d="M209.9 279.9l.5-.1 .3 .2 .1 1.6h-.2v-.2h-.3l.2-.2v-.4l-.7-.1 .2-.1a.35 .35 0 0 0 .4-.1 .35 .35 0 0 0 0-.4l-.6-.1z" fill-rule="evenodd"/>
<path d="M212.3 280h.4z" fill-rule="evenodd"/>
<path d="M212.1 279.8h.2v.3h.3l-.3 .3v.7l.3 .3-.3 .1v.9h-.2z" fill-rule="evenodd"/>
<path d="M212.5 279.8a.57 .57 0 0 1 .7 .6v.7l-.2 .4-.4 .2-.3-.2a.78 .78 0 0 0 .7-.6 .78 .78 0 0 0-.2-.8l-.5-.1z" fill-rule="evenodd"/>
<path d="M213.7 279.8h.4l.3 .2h-.5l-.2 .2-.1 .8 .3 .4h-.3l-.2-.3v-.6z" fill-rule="evenodd"/>
<path d="M214.7 279.9l.6-.1 .3 .5h-.3l-.2-.3h-.4z" fill-rule="evenodd"/>
<path d="M216.5 279.1h.9l.4 .3h-1.1v.9l1 .1-.2 .2h-.8v1h-.2z" fill-rule="evenodd"/>
<path d="M217.2 279.4h.6v.6l-.1 .4-1-.1h.6l.3-.1v-.5l-.2-.3z" fill-rule="evenodd"/>
<path d="M218 279.8h.2l.4 1.5-.2 .3z" fill-rule="evenodd"/>
<path d="M218.9 279.8h.2l-.5 2.2-.4 .1 .2-.2z" fill-rule="evenodd"/>
<path d="M219.3 279.8h.2v.3h.2l-.2 .4v1.1h-.2z" fill-rule="evenodd"/>
<path d="M219.6 279.9l.3-.1v.4l-.4-.1z" fill-rule="evenodd"/>
<path d="M220.3 279.9l.4-.1 .4 .4v.9l-.4 .6h-.3l-.2-.3h.5l.2-.2v-1l-.3-.2h-.4z" fill-rule="evenodd"/>
<path d="M221.4 279.1h.2v.9h.3l-.3 .4v.7l.2 .3h-.2v.2h-.2z" fill-rule="evenodd"/>
<path d="M221.8 279.8l.4 .1a1.57 1.57 0 0 1 .2 1.5l-.4 .3-.4-.2 .4-.1a.93 .93 0 0 0 0-1.4h-.4z" fill-rule="evenodd"/>
<path d="M222.9 279.9l.5-.1 .3 .2 .1 1.6h-.2v-.2h-.3l.2-.2v-.4l-.7-.1 .2-.1a.41 .41 0 0 0 .5-.4l-.2-.2h-.5z" fill-rule="evenodd"/>
<path d="M225.3 280h.4z" fill-rule="evenodd"/>
<path d="M225.1 279.8h.2v.3h.3l-.3 .3v.7l.3 .3-.3 .1v.9h-.2z" fill-rule="evenodd"/>
<path d="M225.3 280l.2-.2a.57 .57 0 0 1 .7 .6v.7l-.2 .4-.4 .2-.3-.2a.78 .78 0 0 0 .7-.6 .78 .78 0 0 0-.2-.8z" fill-rule="evenodd"/>
<path d="M226.5 280l.4-.2 .5 .2h-.5l-.2 .3-.1 .7 .3 .4h-.3l-.2-.3z" fill-rule="evenodd"/>
<path d="M227.7 279.9l.6-.1 .3 .5h-.3l-.2-.3h-.4z" fill-rule="evenodd"/>
<path d="M203.6 293.8l1.2 .1 .3 .4h-1.2v1.3h1.2l-.4 .4h-.8v1.4h-.3z" fill-rule="evenodd"/>
<path d="M205.1 282.1h.4l-.3 .3h-.1z" fill-rule="evenodd"/>
<path d="M204.6 294.3h.5l.2 .8-.2 .5h-1.2h.6a.71 .71 0 0 0 .5-.7 .71 .71 0 0 0-.4-.6z" fill-rule="evenodd"/>
<path d="M205.6 294.9h.3v2.5h-.3z" fill-rule="evenodd"/>
<path d="M205.6 293.8h.3v.5h-.3z" fill-rule="evenodd"/>
<path d="M206.4 295.1h.5a.61 .61 0 0 0-.4 .8h1.1v.3h-1.1a.86 .86 0 0 0 .4 .9h-.5l-.1-.2-.1-1.2z" fill-rule="evenodd"/>
<path d="M206.5 294.9l.4-.1 .3 .1 .4 .5v.5h-1.1h.9l-.2-.6-.2-.2h-.6z" fill-rule="evenodd"/>
<path d="M207.1 280.1l.5-.1-.1 .1a.99 .99 0 0 0-.2 1.1l.3 .2h-.4l-.1-.2-.1-.7z" fill-rule="evenodd"/>
<path d="M206.4 297.1h.7l.2-.5 .3 .2a.68 .68 0 0 1-.9 .6z" fill-rule="evenodd"/>
<path d="M208.6 281.4h.4z" fill-rule="evenodd"/>
<path d="M208.9 295.2l.3-.1-1 2-.3 .3v-.3z" fill-rule="evenodd"/>
<path d="M207.9 294.9h1.3v.2l-1.3 .1z" fill-rule="evenodd"/>
<path d="M207.9 297.4l.3-.3h1.1v.3z" fill-rule="evenodd"/>
<path d="M209.6 295.1h.5a1.33 1.33 0 0 0-.3 1.8l.3 .2h-.5l-.1-.2-.1-1.2z" fill-rule="evenodd"/>
<path d="M209.8 280.1l.4-.1-.2 .2-.1 .2-.2-.1z" fill-rule="evenodd"/>
<path d="M209.8 280.8h.7h-.1a.36 .36 0 0 0-.4 .2 .36 .36 0 0 0 .1 .4l.4 .1-.3 .2-.3-.1-.2-.3z" fill-rule="evenodd"/>
<path d="M209.6 295.1a.69 .69 0 0 1 .8-.3 .69 .69 0 0 1 .5 .7l-.1 1.3a.63 .63 0 0 1-.4 .6 .63 .63 0 0 1-.8-.3h.8l.2-.5-.1-1.2-.3-.3z" fill-rule="evenodd"/>
<path d="M210.1 281.4h.5z" fill-rule="evenodd"/>
<path d="M211.1 279.1h.2v2.5h-.2z" fill-rule="evenodd"/>
<path d="M211.2 296.3l.2-.1 .2 .6 .5 .3h-.8z" fill-rule="evenodd"/>
<path d="M211.6 279.1h.2v2.5h-.2z" fill-rule="evenodd"/>
<path d="M211.5 294l.2-.2h.5l.5 .4h-.9a.63 .63 0 0 0-.2 .8 .63 .63 0 0 0 .6 .4l.6 .4 .1 .8-.3 .7-.3 .2-.6-.1-.4-.3h.8a.67 .67 0 0 0 .5-.8 .67 .67 0 0 0-.7-.6l-.4-.1-.3-.5 .1-.7z" fill-rule="evenodd"/>
<path d="M212.2 294.2h.5l.2 .7h-.3l-.2-.5z" fill-rule="evenodd"/>
<path d="M213.3 294.2l.3-.3v1h.3v.3h-.3v1.7l.1 .2h-.4v-1.9h-.2v-.3h.2z" fill-rule="evenodd"/>
<path d="M213.3 297.1h.6l-.1 .3a.35 .35 0 0 1-.4 0 .35 .35 0 0 1-.1-.3z" fill-rule="evenodd"/>
<path d="M214.2 295.1h.6a.44 .44 0 0 0-.5 .6l-.2-.1z" fill-rule="evenodd"/>
<path d="M214.2 296.1h.9a.95 .95 0 0 0-.8 .7l.1 .3 .7 .1-.2 .1a.55 .55 0 0 1-.9-.2v-.6z" fill-rule="evenodd"/>
<path d="M213.6 281.4h.4l.2-.4h.3l-.2 .5-.2 .2h-.3z" fill-rule="evenodd"/>
<path d="M214 280h.4l.1 .4h-.3z" fill-rule="evenodd"/>
<path d="M214.6 280.1l.5-.1-.2 .1a.41 .41 0 0 0 .4 .5l.3 .4-.1 .5-.3 .2h-.3l-.2-.3h.5a.37 .37 0 0 0 .1-.4 .37 .37 0 0 0-.4-.2l-.3-.3z" fill-rule="evenodd"/>
<path d="M214.6 297.1h.5z" fill-rule="evenodd"/>
<path d="M214.2 295.1l.2-.2a.62 .62 0 0 1 1 .4l.1 2.1h-.3l-.1-.3h-.3l.3-.3v-.7h-.9l.4-.1a.42 .42 0 0 0 .6-.3 .42 .42 0 0 0-.4-.6h-.6z" fill-rule="evenodd"/>
<path d="M214.6 281.1h.2l.2 .3h-.3z" fill-rule="evenodd"/>
<path d="M215.8 294.9h.3v.3h.2l-.2 .6v1.6h-.3z" fill-rule="evenodd"/>
<path d="M216.1 295.1h.4l-.2 .1h-.2z" fill-rule="evenodd"/>
<path d="M216.2 295a.52 .52 0 0 1 .6-.2 .52 .52 0 0 1 .3 .6v2h-.3v-2l-.1-.2-.6-.1z" fill-rule="evenodd"/>
<path d="M218.1 282.1h.4l-.3 .3h-.1z" fill-rule="evenodd"/>
<path d="M217.7 294.9l.2-.1a.44 .44 0 0 1 .6 .3l-.6 .1-.1 .2-.1 1.2 .4 .5h-.5l-.2-.6v-.8z" fill-rule="evenodd"/>
<path d="M217.6 297.1h1a.42 .42 0 0 1-.7 .3z" fill-rule="evenodd"/>
<path d="M218.5 293.8h.3v3.6h-.2v-.3h-.4a1.48 1.48 0 0 0 0-2h.3z" fill-rule="evenodd"/>
<path d="M219.3 295.1h.5l-.2 .1-.1 .5-.3-.1z" fill-rule="evenodd"/>
<path d="M219.3 296.2l.9-.1-.2 .1a.47 .47 0 0 0-.6 .3 .47 .47 0 0 0 .4 .6l.4 .1a.55 .55 0 0 1-.9 .1l-.2-.4z" fill-rule="evenodd"/>
<path d="M219.4 294.9a.67 .67 0 0 1 .7-.1 .67 .67 0 0 1 .4 .6l.1 2h-.3v-.3h-.4l.3-.4v-.6h-.8l.8-.3v-.4l-.2-.3h-.7z" fill-rule="evenodd"/>
<path d="M219.8 297.1h.5z" fill-rule="evenodd"/>
<path d="M220.1 280.1l.5-.1-.1 .1a.99 .99 0 0 0-.2 1.1l.3 .2h-.4l-.2-.2v-.7z" fill-rule="evenodd"/>
<path d="M220.9 293.8h.3v3.6h-.3z" fill-rule="evenodd"/>
<path d="M221.7 295.2l.5-.1-.2 .2-.2 .5v.9l.4 .4h-.5l-.1-.3-.1-.8z" fill-rule="evenodd"/>
<path d="M221.6 281.4h.4z" fill-rule="evenodd"/>
<path d="M221.8 294.9l.5-.1a.74 .74 0 0 1 .6 .6l.1 .7-.1 .9-.3 .4-.5 .1-.4-.4h.6l.3-.2 .1-1.1-.1-.4-.3-.3h-.6z" fill-rule="evenodd"/>
<path d="M222.8 280.1l.4-.1-.2 .2-.1 .2-.2-.1z" fill-rule="evenodd"/>
<path d="M222.8 280.8h.7h-.1a.36 .36 0 0 0-.5 .2 .36 .36 0 0 0 .2 .4l.4 .1-.3 .2-.3-.1-.2-.3z" fill-rule="evenodd"/>
<path d="M223.1 281.4h.5z" fill-rule="evenodd"/>
<path d="M223.3 294.9h.3v.3h.2l-.2 .6v1.6h-.3z" fill-rule="evenodd"/>
<path d="M223.6 295.1h.4l-.2 .1h-.2z" fill-rule="evenodd"/>
<path d="M223.6 295a.52 .52 0 0 1 .7-.2 .52 .52 0 0 1 .3 .6v2h-.3v-2l-.3-.3h-.4z" fill-rule="evenodd"/>
<path d="M224.1 279.1h.2v2.5h-.2z" fill-rule="evenodd"/>
<path d="M224.6 279.1h.2v2.5h-.2z" fill-rule="evenodd"/>
<path d="M225.1 295.1h.6l-.4 .3-.1 .5 1.2 .1v.2h-1.2l.1 .7 .4 .2h-.6l-.1-.3-.1-1z" fill-rule="evenodd"/>
<path d="M225.3 294.9a.7 .7 0 0 1 1 .6l.1 .4h-1.2h.9l-.1-.5-.2-.3h-.7z" fill-rule="evenodd"/>
<path d="M225.1 297.1h.7l.3-.5 .3 .1-.3 .6-.2 .2h-.4z" fill-rule="evenodd"/>
<path d="M226.5 298.1h1.8v.4h-1.8z" fill-rule="evenodd"/>
<path d="M226.6 281.4h.4l.2-.4h.3l-.1 .3-.3 .4h-.3z" fill-rule="evenodd"/>
<path d="M227 280h.4l.1 .4h-.3z" fill-rule="evenodd"/>
<path d="M227.6 280.1l.5-.1-.2 .1a.41 .41 0 0 0 .4 .5l.3 .4-.1 .5-.3 .2h-.3l-.2-.3h.5a.37 .37 0 0 0 .1-.4 .37 .37 0 0 0-.4-.2l-.3-.3z" fill-rule="evenodd"/>
<path d="M227.6 281.1h.2l.2 .3h-.3z" fill-rule="evenodd"/>
<path d="M228.4 293.8l1.2 .1 .4 .4h-1.3v1.3h1.3l-.4 .4h-.9v1.4h-.3z" fill-rule="evenodd"/>
<path d="M229.4 294.3h.6l.1 .8-.1 .5h-1.3h.7a.49 .49 0 0 0 .4-.5l-.1-.7z" fill-rule="evenodd"/>
<path d="M230.3 293.8h1.8v.5h-.7v3.1h-.3v-3.1h-.8z" fill-rule="evenodd"/>
<path d="M232.5 294.7l.1-.1h.4l-.5 .5z" fill-rule="evenodd"/>
<path d="M233.1 293.8h.2v3.6h-.3v-2.8h-.4z" fill-rule="evenodd"/>
<path d="M234.2 294.2h.5l-.4 .4-.1 1.6a.96 .96 0 0 0 .5 .9l-.5 .1-.2-.5v-1.8z" fill-rule="evenodd"/>
<path d="M234.3 294h.1a.51 .51 0 0 1 .5-.1 .51 .51 0 0 1 .3 .4l.2 .7-.1 1.7-.3 .7-.5 .1-.3-.3 .5-.1 .3-.4v-1.9a.45 .45 0 0 0-.3-.6h-.5z" fill-rule="evenodd"/>
<path d="M235.9 294.2h.5l-.3 .1-.1 .5v1.8a.46 .46 0 0 0 .4 .5l-.5 .1-.2-.6v-1.6z" fill-rule="evenodd"/>
<path d="M236 294h.1a.41 .41 0 0 1 .7 0l.3 .9-.1 1.9a.61 .61 0 0 1-.4 .6 .61 .61 0 0 1-.6-.1l-.1-.1 .5-.1 .2-.1 .2-.8-.1-1.6-.3-.4h-.5z" fill-rule="evenodd"/>
<path d="M237.2 298.1h1.8v.4h-1.8z" fill-rule="evenodd"/>
<path d="M239.3 294.7l.1-.1h.4l-.5 .5z" fill-rule="evenodd"/>
<path d="M239.9 293.8h.2v3.6h-.3v-2.8h-.4z" fill-rule="evenodd"/>
<path d="M240.9 296.9h.3v.5h-.3z" fill-rule="evenodd"/>
<path d="M241.8 294.7l.2-.1h.4l-.5 .5z" fill-rule="evenodd"/>
<path d="M242.4 293.8h.2v3.6h-.2v-2.8h-.4z" fill-rule="evenodd"/>
<path d="M243.5 296.9h.3v.5h-.3z" fill-rule="evenodd"/>
<path d="M244.4 294.7l.2-.1h.3l-.5 .5z" fill-rule="evenodd"/>
<path d="M245 293.8h.2v3.6h-.3v-2.8h-.3z" fill-rule="evenodd"/>
</g>
<use href="#words"/>
</svg>
